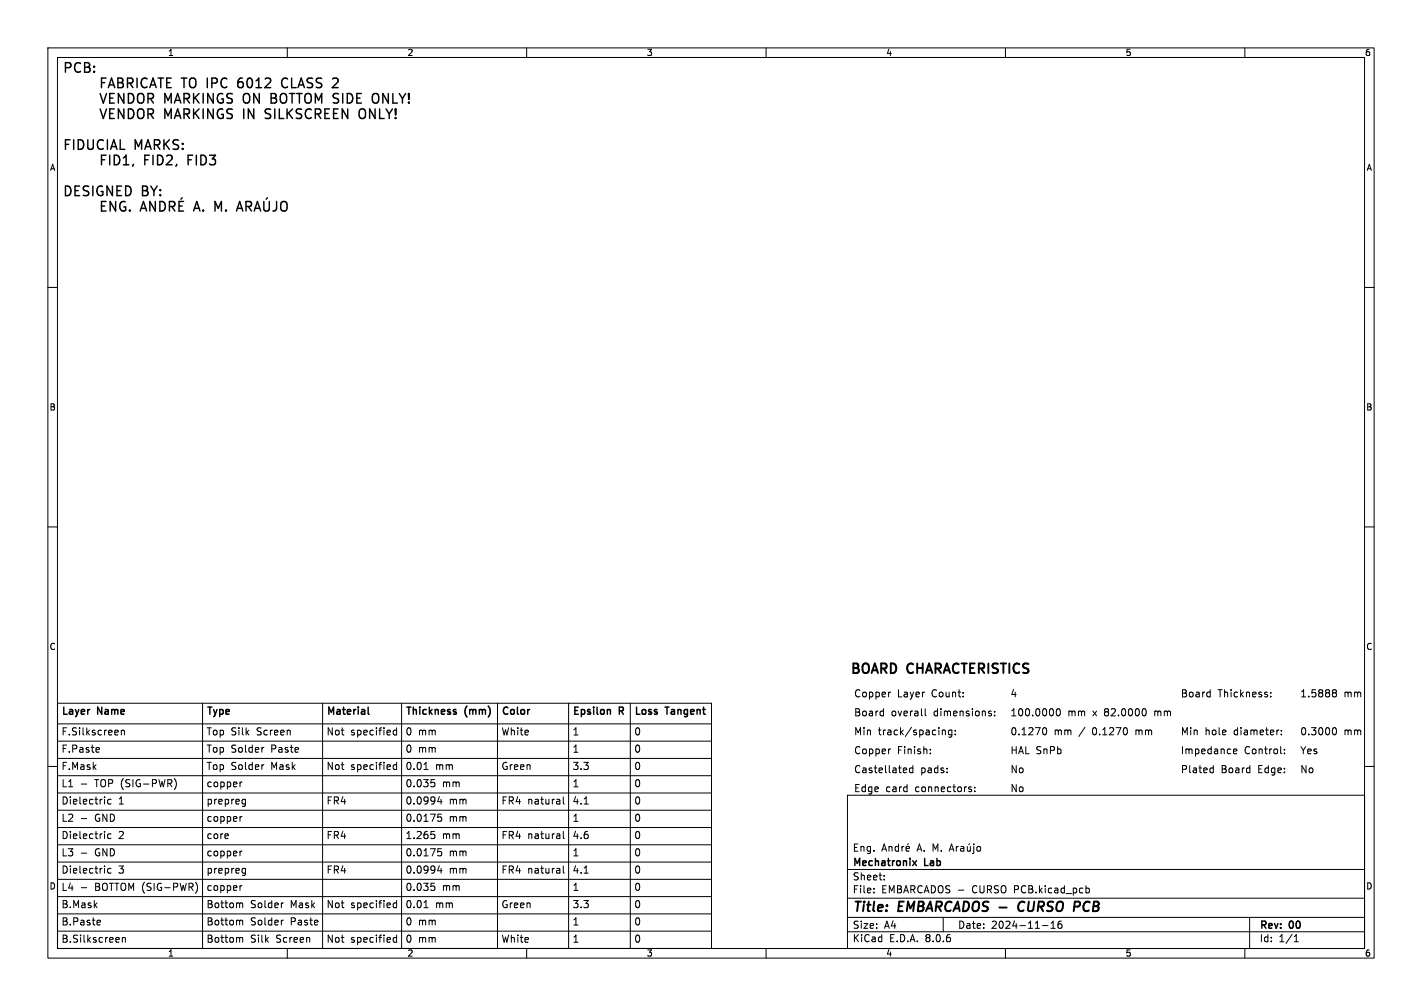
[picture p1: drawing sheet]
<svg xmlns="http://www.w3.org/2000/svg" width="297mm" height="210mm" viewBox="0 0 297 210" stroke-linecap="round" stroke-linejoin="round" font-family="sans-serif">
<defs><g id="words">
<g font-size="2.8">
<text x="13" y="15.9">PCB:</text>
<text x="13" y="19.1">FABRICATE</text>
<text x="13" y="22.3">VENDOR</text>
<text x="34.3" y="22.3">MARKINGS</text>
<text x="38" y="19.1">TO IPC</text>
<text x="50.6" y="19.1">6012</text>
<text x="51.2" y="22.3">ON</text>
<text x="57.5" y="22.3">BOTTOM SIDE</text>
<text x="60.2" y="19.1">CLASS</text>
<text x="71.4" y="19.1">2</text>
<text x="79.7" y="22.3">ONLY!</text>
<text x="13" y="25.6">VENDOR</text>
<text x="34.3" y="25.6">MARKINGS</text>
<text x="51.2" y="25.6">IN</text>
<text x="56.3" y="25.6">SILKSCREEN</text>
<text x="76.4" y="25.6">ONLY!</text>
<text x="13" y="32">FIDUCIAL</text>
<text x="28.1" y="32">MARKS:</text>
<text x="30.1" y="35.2">FID2,</text>
<text x="39.6" y="35.2">FID3</text>
<text x="13" y="41.7">DESIGNED</text>
<text x="29.6" y="41.7">BY:</text>
<text x="41" y="44.9">A.</text>
<text x="177.5" y="141.6">BOARD</text>
<text x="189.6" y="141.6">CHARACTERISTICS</text>
<text x="178" y="190.9">Title:</text>
<text x="187.7" y="190.9">EMBARCADOS -</text>
<text x="214.3" y="190.9">CURSO</text>
<text x="226.7" y="190.9">PCB</text>
</g>
<g font-size="2.1">
<text x="12.8" y="150">Layer</text>
<text x="20.4" y="150">Name</text>
<text x="43.1" y="150">Type</text>
<text x="68.1" y="150">Material</text>
<text x="84.6" y="150">Thickness</text>
<text x="97.2" y="150">(mm)</text>
<text x="104.7" y="150">Color</text>
<text x="119.5" y="150">Epsilon</text>
<text x="129.4" y="150">R</text>
<text x="132.4" y="150">Loss</text>
<text x="139.1" y="150">Tangent</text>
<text x="178.3" y="150">Board</text>
<text x="178.3" y="146">Copper</text>
<text x="186.2" y="150">overall</text>
<text x="187.5" y="146">Layer</text>
<text x="194.9" y="146">Count:</text>
<text x="195.3" y="150">dimensions:</text>
<text x="210.9" y="150">100.0000</text>
<text x="210.9" y="146">4</text>
<text x="223.1" y="150">mm</text>
<text x="228.5" y="150">x</text>
<text x="231.2" y="150">82.0000</text>
<text x="241.9" y="150">mm</text>
<text x="246.5" y="146">Board</text>
<text x="254.4" y="146">Thickness:</text>
<text x="271.4" y="146">1.5888</text>
<text x="280.7" y="146">mm</text>
<text x="12.8" y="153.7">F.Silkscreen</text>
<text x="43.1" y="153.7">Top Silk</text>
<text x="53.3" y="153.7">Screen</text>
<text x="68.1" y="153.7">Not</text>
<text x="73.1" y="153.7">specified</text>
<text x="84.6" y="153.7">0 mm</text>
<text x="104.7" y="153.7">White</text>
<text x="119.5" y="153.7">1</text>
<text x="132.4" y="153.7">0</text>
<text x="178.3" y="153.9">Min</text>
<text x="183.5" y="153.9">track/spacing:</text>
<text x="210.9" y="153.9">0.1270</text>
<text x="220.2" y="153.9">mm</text>
<text x="225.7" y="153.9">/</text>
<text x="228.7" y="153.9">0.1270</text>
<text x="238" y="153.9">mm</text>
<text x="246.5" y="153.9">Min</text>
<text x="251.7" y="153.9">hole</text>
<text x="257.9" y="153.9">diameter:</text>
<text x="271.4" y="153.9">0.3000</text>
<text x="280.7" y="153.9">mm</text>
<text x="12.8" y="157.3">F.Paste</text>
<text x="12.8" y="160.9">F.Mask</text>
<text x="43.1" y="157.3">Top Solder</text>
<text x="43.1" y="160.9">Top Solder</text>
<text x="56.3" y="157.3">Paste</text>
<text x="56.3" y="160.9">Mask</text>
<text x="68.1" y="160.9">Not</text>
<text x="73.1" y="160.9">specified</text>
<text x="84.6" y="160.9">0.01</text>
<text x="84.6" y="157.3">0 mm</text>
<text x="90.8" y="160.9">mm</text>
<text x="104.7" y="160.9">Green</text>
<text x="119.5" y="157.3">1</text>
<text x="119.5" y="160.9">3.3</text>
<text x="132.4" y="160.9">0</text>
<text x="132.4" y="157.3">0</text>
<text x="178.3" y="157.9">Copper</text>
<text x="178.3" y="161.9">Castellated</text>
<text x="187.5" y="157.9">Finish:</text>
<text x="192.3" y="161.9">pads:</text>
<text x="210.9" y="161.9">No</text>
<text x="210.9" y="157.9">HAL SnPb</text>
<text x="246.5" y="157.9">Impedance</text>
<text x="246.5" y="161.9">Plated</text>
<text x="255.1" y="161.9">Board</text>
<text x="259.9" y="157.9">Control:</text>
<text x="263" y="161.9">Edge:</text>
<text x="271.4" y="157.9">Yes</text>
<text x="271.4" y="161.9">No</text>
<text x="12.8" y="164.5">L1</text>
<text x="19.6" y="164.5">TOP (SIG-PWR)</text>
<text x="43.1" y="164.5">copper</text>
<text x="84.6" y="164.5">0.035</text>
<text x="92.2" y="164.5">mm</text>
<text x="119.5" y="164.5">1</text>
<text x="132.4" y="164.5">0</text>
<text x="178.3" y="165.8">Edge</text>
<text x="185" y="165.8">card</text>
<text x="191.4" y="165.8">connectors:</text>
<text x="210.9" y="165.8">No</text>
<text x="12.8" y="168.1">Dielectric</text>
<text x="12.8" y="171.7">L2</text>
<text x="19.6" y="171.7">GND</text>
<text x="24.6" y="168.1">1</text>
<text x="43.1" y="168.1">prepreg</text>
<text x="43.1" y="171.7">copper</text>
<text x="68.1" y="168.1">FR4</text>
<text x="84.6" y="168.1">0.0994</text>
<text x="84.6" y="171.7">0.0175</text>
<text x="93.6" y="168.1">mm</text>
<text x="93.6" y="171.7">mm</text>
<text x="104.7" y="168.1">FR4 natural</text>
<text x="119.5" y="168.1">4.1</text>
<text x="119.5" y="171.7">1</text>
<text x="132.4" y="168.1">0</text>
<text x="132.4" y="171.7">0</text>
<text x="12.8" y="178.9">L3</text>
<text x="12.8" y="175.3">Dielectric</text>
<text x="19.6" y="178.9">GND</text>
<text x="24.6" y="175.3">2</text>
<text x="43.1" y="178.9">copper</text>
<text x="43.1" y="175.3">core</text>
<text x="68.1" y="175.3">FR4</text>
<text x="84.6" y="178.9">0.0175</text>
<text x="84.6" y="175.3">1.265</text>
<text x="92.2" y="175.3">mm</text>
<text x="93.6" y="178.9">mm</text>
<text x="104.7" y="175.3">FR4 natural</text>
<text x="119.5" y="175.3">4.6</text>
<text x="119.5" y="178.9">1</text>
<text x="132.4" y="175.3">0</text>
<text x="132.4" y="178.9">0</text>
<text x="178" y="178">Eng.</text>
<text x="191.6" y="178">A.</text>
<text x="12.8" y="182.5">Dielectric</text>
<text x="24.6" y="182.5">3</text>
<text x="43.1" y="182.5">prepreg</text>
<text x="68.1" y="182.5">FR4</text>
<text x="84.6" y="182.5">0.0994</text>
<text x="93.6" y="182.5">mm</text>
<text x="104.7" y="182.5">FR4 natural</text>
<text x="119.5" y="182.5">4.1</text>
<text x="132.4" y="182.5">0</text>
<text x="178" y="184">Sheet:</text>
<text x="178" y="181.2">Mechatronix</text>
<text x="193.2" y="181.2">Lab</text>
<text x="12.8" y="186.1">L4</text>
<text x="12.8" y="189.7">B.Mask</text>
<text x="19.6" y="186.1">BOTTOM (SIG-PWR)</text>
<text x="43.1" y="189.7">Bottom</text>
<text x="43.1" y="186.1">copper</text>
<text x="52.1" y="189.7">Solder</text>
<text x="60.4" y="189.7">Mask</text>
<text x="68.1" y="189.7">Not</text>
<text x="73.1" y="189.7">specified</text>
<text x="84.6" y="189.7">0.01</text>
<text x="84.6" y="186.1">0.035</text>
<text x="90.8" y="189.7">mm</text>
<text x="92.2" y="186.1">mm</text>
<text x="104.7" y="189.7">Green</text>
<text x="119.5" y="186.1">1</text>
<text x="119.5" y="189.7">3.3</text>
<text x="132.4" y="186.1">0</text>
<text x="132.4" y="189.7">0</text>
<text x="178" y="186.7">File:</text>
<text x="184.1" y="186.7">EMBARCADOS -</text>
<text x="203.2" y="186.7">CURSO PCB.kicad_pcb</text>
<text x="12.8" y="193.3">B.Paste</text>
<text x="12.8" y="196.9">B.Silkscreen</text>
<text x="43.1" y="196.9">Bottom</text>
<text x="43.1" y="193.3">Bottom</text>
<text x="52.1" y="196.9">Silk</text>
<text x="52.1" y="193.3">Solder</text>
<text x="57.4" y="196.9">Screen</text>
<text x="60.4" y="193.3">Paste</text>
<text x="68.1" y="196.9">Not</text>
<text x="73.1" y="196.9">specified</text>
<text x="84.6" y="196.9">0 mm</text>
<text x="84.6" y="193.3">0 mm</text>
<text x="104.7" y="196.9">White</text>
<text x="119.5" y="196.9">1</text>
<text x="119.5" y="193.3">1</text>
<text x="132.4" y="196.9">0</text>
<text x="132.4" y="193.3">0</text>
<text x="178" y="196.9">KiCad</text>
<text x="178" y="194.1">Size:</text>
<text x="184.7" y="194.1">A4</text>
<text x="185.7" y="196.9">E.D.A.</text>
<text x="193.3" y="196.9">8.0.6</text>
<text x="200" y="194.1">Date:</text>
<text x="207" y="194.1">2024-11-16</text>
<text x="263" y="194.3">Rev:</text>
<text x="263" y="196.9">Id:</text>
<text x="267.1" y="196.9">1/1</text>
<text x="269.4" y="194.3">00</text>
</g>
<g font-size="1.8">
<text x="35" y="11.9">1</text>
<text x="85" y="11.9">2</text>
<text x="135" y="11.9">3</text>
<text x="185" y="11.9">4</text>
<text x="235" y="11.9">5</text>
<text x="285" y="11.9">6</text>
<text x="10.3" y="35.9">A</text>
<text x="285.4" y="35.9">A</text>
<text x="10.3" y="85.9">B</text>
<text x="285.3" y="85.9">B</text>
<text x="10.3" y="135.9">C</text>
<text x="285.3" y="135.9">C</text>
<text x="10.3" y="185.9">D</text>
<text x="285.3" y="185.9">D</text>
<text x="35" y="199.9">1</text>
<text x="85" y="199.9">2</text>
<text x="135" y="199.9">3</text>
<text x="185" y="199.9">4</text>
<text x="235" y="199.9">5</text>
<text x="285" y="199.9">6</text>
</g>
</g></defs>
<g fill="none" stroke="#000" stroke-width=".21">
<path d="M10 10h277v190h-277zM12 12h273v186h-273zM60 10v2M110 10v2M160 10v2M210 10v2M260 10v2M10 60h2M285 60h2M10 110h2M285 110h2M10 160h2"/>
<path d="M12 146.8h136.6v51.2h-136.6zM12 158.3h136.6M12 151.1h136.6M12 154.7h136.6M20.6 156l.2 .4-.7 .1M20.7 157h-.1M25.3 152.6l.3-.2 .3 .1 .1 .9M25.3 152.4v1M42.3 146.8v51.2M55.1 156l-.3 .2M55.1 159.6l-.3 .2M60.6 152.5v.9"/>
<path d="M62.3 156.1v.3l-.7 .1M67.4 146.8v51.2M82.8 151.9v1.5M82.8 159.1v1.5M82.8 152.5l-.4-.1-.3 .3 .2 .7h.5M82.8 159.7l-.4-.1-.3 .3 .2 .7h.5M83.9 146.8v51.2M103.9 146.8v51.2M118.8 146.8v51.2M131.6 146.8v51.2M184.4 148.4l.1 .1M184.5 147.9v1.5"/>
<path d="M184.5 149.4h-.1M186 156.4h-.3M186 144.5l-.3 .1M190.7 159.8v1.5M193.2 147.9v1.3l.3 .2M194.3 157.2v.2M194.3 156.4v.2M196.9 152.5h.5l.1 .9M198.8 152.5l-.4-.1-.3 .3 .1 .6h.6M198.8 152.4v1.2l-.3 .3-.3-.1M199.5 153.3v.1M199.5 152.5v.1"/>
<path d="M206.9 148.9l.2 .3-.2 .2M206.9 148.4l.1 .1M207.7 149.3v.1M207.7 148.5v.2M217.9 152l.2-.1a.8 .8 0 0 1 .5 .7 .8 .8 0 0 1-.5 .8l-.2-.1M220.8 148.1l.2-.2a.8 .8 0 0 1 .5 .8 .8 .8 0 0 1-.5 .7l-.2-.1-.2-.4zM237.3 152.4v1M237.5 152.4l-.2 .1M239.3 148.2v1M241.2 148.4v1M241.4 148.4l-.2 .2M252.6 144.5l.2 .1"/>
<path d="M252.8 144v1.5M252.8 145.4l-.2 .1M253.4 159.8v1.5M257.6 156.9l.7-.2v-.3h-.5l-.2 .2 .1 .7h.6M265.4 145.3v.2M265.4 144.6v.1M267.6 153.3v.1M267.6 152.5v.1M268.3 157.2v.2M268.3 156.4v.2M278.4 152l.2-.1a.8 .8 0 0 1 .6 .7 .8 .8 0 0 1-.6 .8l-.2-.1M278.4 144.1l.5-.1 .2 .1v.2l-.2 .3"/>
<path d="M278.4 144.6h.2M278.6 144.6h.3M278.6 144.6l-.2 .1M278.9 144.6l.2 .3v.4l-.2 .2-.5-.1M285 160h2M12 172.7h136.6M12 176.4h136.6M12 169.1h136.6M12 165.5h136.6M12 180h136.6M12 161.9h136.6M17 178.1h1.1"/>
<path d="M17 170.9h1.1M17 163.7h1.1M23.2 166.9h-.4l-.3 .2 .1 .7h.6M23.2 174.1h-.4l-.3 .3 .1 .6h.6M36.4 162.5a1.72 1.72 0 0 1 0 2.3M50.6 177.7l-.5 .3M50.6 170.5l-.5 .2M50.6 163.2l-.5 .3M50.8 166.9h.5M51.3 166.9v1.2l-.2 .2-.3 .1M51.3 167.8l-.5 .1M88.5 160.6h.9"/>
<path d="M90.1 162.7h.7M90.1 173.6h.7M90.2 163.3h.3l.3 .3v.5l-.6 .1M90.2 174.1h.3l.3 .3v.5l-.6 .2M91.5 170h.7M91.5 177.2h.7M91.6 170.5h.4l.3 .3-.2 .6-.5 .1M91.6 177.7h.4l.3 .3-.2 .6-.5 .1M91.8 166.3l-.4 1.1h.9M92.1 166.9v1M117.7 166.4v1.2l.2 .3M117.7 173.6v1.3l.2 .2"/>
<path d="M122 167.9h.9M177 166h108v32h-108zM184.2 177.7l.5-1.5 .5 1.5M184.3 177.3h.7M185.7 176.7v1M185.7 176.8l.2-.1 .3 .1 .1 .9M187.7 176.8l-.5-.1-.2 .3 .1 .6h.6M187.7 176.2v1.5M188.4 176.7v1M188.8 176.7l-.4 .3M189.2 177.2l.8-.1-.1-.3-.4-.1-.3 .2 .1 .7h.6M189.3 160.4l.1 .3-.7 .1"/>
<path d="M189.7 176.1l-.2 .2M190.7 160.4l-.5-.1-.2 .3 .1 .6h.6M194.9 177.7v-1.5l.5 1.1 .5-1.1v1.5M196.6 177.6v.1M198.2 177.7l.5-1.5 .5 1.5M198.4 177.3h.7M199.7 176.7v1M200.2 176.7l-.5 .3M200.7 176.8h.5l.1 .9M201.3 177.1h-.5l-.2 .2 .2 .4 .5-.1M202 176.7l.1 .9 .4 .1 .2-.1M202.5 176.1l-.2 .2"/>
<path d="M202.7 176.7v1M202.7 164.8l.3 .2-.3 .3M202.7 164.3h.2M203.4 176.2v.1M203.4 176.7v1.3l-.3 .2M203.6 164.3v.2M203.6 165.1v.2M204.2 176.8l.3-.1 .3 .3v.4l-.3 .3-.3-.1-.2-.2zM253 160.3l.4 .1M253.4 161.2l-.4 .1M12 190.8h136.6M12 183.6h136.6"/>
<path d="M12 187.2h136.6M12 194.4h136.6M17 185.3h1.1M20.5 192.1l.4 .1 .1 .3-.7 .1M20.9 193l-.4 .1M23.2 181.3h-.4l-.3 .3 .1 .6h.6M25.6 195.8l.2-.1 .3 .1 .1 .9M25.6 195.7v1M40.8 184.2a1.72 1.72 0 0 1 0 2.3M50.3 188.5l.4 .2v.8M50.3 195.7l.4 .2v.8M50.3 192.1l.4 .2v.8"/>
<path d="M50.6 184.9l-.5 .3M50.8 181.3h.5M51.3 181.3v1.2l-.2 .2-.3 .1M51.3 182.2l-.5 .1M59.2 188.5l-.4 .1M59.2 192.1l-.4 .1M60 198v2M64.6 195.8l.1 .9M66.3 192.2l.1 .3-.7 .1M82.8 188v1.5M82.8 195.2v1.5M82.8 188.6l-.4-.1-.3 .3 .2 .6h.5"/>
<path d="M82.8 195.8l-.4-.1-.3 .3 .2 .6h.5M88.5 189.5h.9M90.1 184.4h.7M90.2 185h.3l.3 .2-.1 .6-.5 .1M91.8 180.7l-.4 1.1h.9M92.1 181.3v1M110 198v2M117.7 180.8v1.3l.2 .2M122 182.3h.9M160 198v2M177 194.5h108M177 191.5h108"/>
<path d="M177 187.5h108M177 181.5h108M182.5 186.3v.1M182.5 185.5v.1M184.7 183.6v.1M184.7 182.8v.1M197 191.5v3M210 198v2M217.7 193.2h1.2M219.5 193.8h.9M219.5 192.7l.5-.4v1.5M221.7 192.3l-.5 .1a1.01 1.01 0 0 0 0 1.4l.5-.1 .1-.5-.3-.3h-.3l-.2 .3"/>
<path d="M227 185.4l.4 .1 .1 .2v.6l-.5 .1M260 198v2M261 191.5v6.5M270.3 196.6h.9M270.3 195.5l.4-.4v1.5"/>
</g>
<g fill="none" stroke="#000" stroke-width=".4">
<path d="M179.2 138.7l-.3-.2h-.7v2M180.2 138.8a.68 .68 0 0 1 1.2 0M185.1 138.7l-.3-.2h-.8v2M187 138.8l-.5-.3h-.5v2M190.7 138.7l-.1-.1a.72 .72 0 0 0-.9 .2M191.6 138.5v2M192.7 138.5v2M196.4 138.7l-.3-.2h-.7v2M200.2 138.7l-.1-.1a.72 .72 0 0 0-.9 .2M200.8 138.5h1.2M201.4 138.5v2M203.6 138.5h-1v2"/>
<path d="M205.5 138.7l-.3-.2h-.8v2M206.4 138.5v2M208.4 138.6l-.7-.1-.3 .2M209 138.5h1.1M209.6 138.5v2M210.8 138.5v2M212.9 138.7l-.1-.1a.72 .72 0 0 0-.9 .2M214.8 138.6l-.8-.1-.2 .2M182 140.5l.7-2 .7 2M193.4 140.5l.6-2 .7 2M197.1 140.5l.7-2 .6 2M213.6 188.2a1.07 1.07 0 0 0-.9 .8 1.07 1.07 0 0 0 .5 1.2l.5-.1"/>
<path d="M225.4 188.3a.53 .53 0 0 1 0 .8"/>
</g>
<g fill="none" stroke="#000" stroke-width=".3">
<path d="M24.7 19.5l1.2 2v-2M26.8 19.5v2h.5a1.06 1.06 0 0 0 .6-1.5M29.2 19.5a.67 .67 0 0 1 .9 .7v.7a.67 .67 0 0 1-.7 .6 .67 .67 0 0 1-.7-.6l.1-1.1M30.7 16.5a.8 .8 0 0 0-1 0 .8 .8 0 0 0-.2 .9 .75 .75 0 0 0 .4 .8 .75 .75 0 0 0 .8-.1M31.3 18.3l.7-2 .6 2M31.5 17.7h.9M33 16.3h1.1M33.6 16.3v2M34.8 17.3h.7M35.8 16.3h-1v2h1M49.8 16.8v1.3M49.8 17.3l-.1 .1"/>
<path d="M56.6 19.5v2h.8M59.5 16.3a1.08 1.08 0 0 0-.7 1 1.08 1.08 0 0 0 .7 1M69.8 16.3h.4l.3 .2M70.5 17.2l-1.1 1.1h1.2M78.1 19.6a.67 .67 0 0 1 .9 .2M21.2 33.4h.7M21.2 32.4v2M22.9 32.4v2M23.9 32.4v2h.4a1.06 1.06 0 0 0 .6-1.5M24.7 22.7l1.2 2v-2M25.8 34.4h1.1M26.3 32.4v2"/>
<path d="M26.8 22.7a1.01 1.01 0 0 1 1.2 1 1.01 1.01 0 0 1-1.2 1zM27.9 34.3l-.2 .4M28.8 23a.67 .67 0 0 1 .8-.3 .67 .67 0 0 1 .5 .7v.7a.67 .67 0 0 1-.7 .7 .67 .67 0 0 1-.7-.7zM30.9 20.6h.8a.54 .54 0 0 0 .4-.6 .54 .54 0 0 0-.4-.5h-.8v2M30.9 23.8h.8a.54 .54 0 0 0 .4-.5 .54 .54 0 0 0-.4-.6h-.8v2M31.4 20.6l.7 .9M31.4 23.8l.7 .9M55.4 24.6l.3 .1M55.4 23.3l.1 .2M56.6 20.5h.7M75.1 23a1.35 1.35 0 0 0 .4 1.7h.4M79 21.2a.67 .67 0 0 1-.9 .2"/>
<path d="M21.2 42.1v2h.9M21.2 43h.7M24.1 42.1v2l-1.1-2v2M25.1 42.5a.92 .92 0 0 0 0 1.1 .92 .92 0 0 0 1 .4l.1-.8h-.3M27.1 43.9v.2M29.3 44.1l.7-2 .6 2M29.5 43.5h.9M32.4 42.1v2l-1.1-2v2M33.4 42.1v2h.5a1.06 1.06 0 0 0 .5-1.6M35.4 43.1h.7a.54 .54 0 0 0 .4-.5 .54 .54 0 0 0-.4-.5h-.7v2M35.9 43.1l.6 1M37.4 43h.7"/>
<path d="M38.1 41.3l-.3 .3M38.3 42.1h-.9v2h.9M44.9 44.1v-2l.7 1.4 .6-1.4v2M47.2 43.9v.2M49.4 44.1l.7-2 .6 2M49.6 43.5h.9M51.4 43.1h.7a.54 .54 0 0 0 .4-.5 .54 .54 0 0 0-.4-.5h-.7v2M51.9 43.1l.6 1M53.1 44.1l.7-2 .6 2M53.3 43.5h.9M55.1 42.1v1.6l.4 .4 .6-.1 .1-.3v-1.6M55.9 41.3l-.3 .3"/>
<path d="M57.8 42.1v1.4a.64 .64 0 0 1-.8 .6M58.9 42.2a.66 .66 0 0 1 .7-.1 .66 .66 0 0 1 .4 .6v.7a.67 .67 0 0 1-.7 .7 .67 .67 0 0 1-.7-.7v-.7zM13.3 147.6v1.5M18.6 148.1h.2M21.3 147.6v1.5l-.9-1.5v1.5M43.4 147.6h.9M43.8 147.6v1.5M68.7 149.1v-1.5l.5 1.1 .5-1.1v1.5M71.8 147.6v1.3M74.8 147.6v.2M76.1 148.2l.1 .9M76.2 149l-.2 .1"/>
<path d="M76.2 148.5h-.2M76.9 147.6v1.3l.2 .2M85 147.6h.8M85.4 147.6v1.5M86.3 147.6v1.5M87.7 147.6v.2M89.7 147.6v1.5M94.7 148.4l.6 .4-.2 .3-.4-.1M95.3 148.2l-.4-.1-.2 .2M97.5 147.4l-.2 .4M102 147.4l.3 .4M106.1 147.8l-.5-.2-.3 .2"/>
<path d="M108.1 147.6v1.3M110.6 148.1l-.2 .1M120.8 147.6h-.7v1.5M124 147.6v.2M124.7 147.6v1.3M126.9 148.2h.5l.1 .9M130.1 147.8l-.7-.2v1.5M133 147.6v1.5M138.9 147.6h.8M139.3 147.6v1.5M147 147.6v1.3M190.6 179.7l.8 1"/>
<path d="M191.4 179.7l-.8 1"/>
</g>
<use href="#words"/>
</svg>
